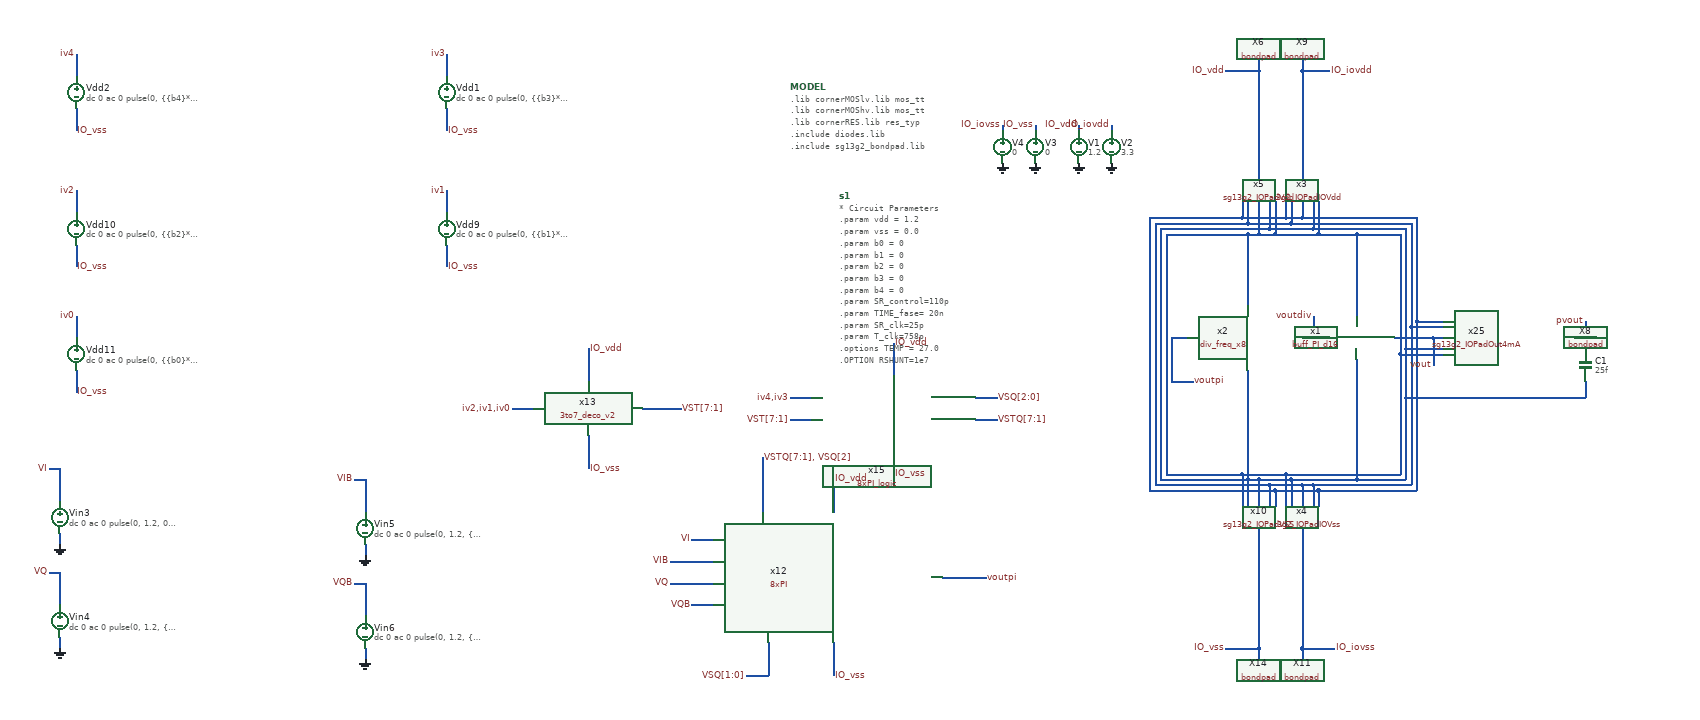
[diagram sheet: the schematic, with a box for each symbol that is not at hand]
v {xschem version=3.4.8RC file_version=1.2}
G {}
K {}
V {}
S {}
F {}
E {}
N 140 -660 220 -660 {lab=IO_vdd}
N 20 -680 240 -680 {lab=IO_iovss}
N 60 -200 240 -200 {lab=IO_iovss}
N 70 -190 250 -190 {lab=IO_iovdd}
N 60 -670 230 -670 {lab=IO_vss}
N -220 -210 -60 -210 {lab=IO_vss}
N 240 -490 240 -200 {lab=IO_iovss}
N -310 -860 -310 -850 {
lab=IO_iovdd}
N -510 -860 -510 -850 {
lab=IO_iovss}
N 10 -720 10 -690 {lab=IO_iovdd}
N -70 -690 10 -690 {lab=IO_iovdd}
N 20 -720 20 -680 {lab=IO_iovss}
N -60 -680 20 -680 {lab=IO_iovss}
N 60 -720 60 -670 {lab=IO_vss}
N -20 -670 60 -670 {lab=IO_vss}
N 70 -720 70 -660 {lab=IO_vdd}
N 40 -690 250 -690 {lab=IO_iovdd}
N 70 -190 70 -160 {lab=IO_iovdd}
N -10 -190 70 -190 {lab=IO_iovdd}
N 60 -200 60 -160 {lab=IO_iovss}
N 40 -200 60 -200 {lab=IO_iovss}
N 10 -220 10 -160 {lab=IO_vdd}
N -70 -220 10 -220 {lab=IO_vdd}
N 40 -960 90 -960 {lab=IO_iovdd}
N 40 -980 40 -960 {lab=IO_iovdd}
N 40 -960 40 -690 {lab=IO_iovdd}
N 10 -690 40 -690 {lab=IO_iovdd}
N -70 -720 -70 -690 {lab=IO_iovdd}
N -240 -690 -70 -690 {lab=IO_iovdd}
N -60 -720 -60 -680 {lab=IO_iovss}
N -230 -680 -60 -680 {lab=IO_iovss}
N -20 -720 -20 -670 {lab=IO_vss}
N -220 -670 -20 -670 {lab=IO_vss}
N -10 -720 -10 -660 {lab=IO_vdd}
N -40 -960 -40 -660 {lab=IO_vdd}
N -60 -660 -40 -660 {lab=IO_vdd}
N -370 -860 -370 -850 {
lab=IO_vdd}
N -450 -860 -450 -850 {
lab=IO_vss}
N -10 -190 -10 -160 {lab=IO_iovdd}
N -240 -190 -10 -190 {lab=IO_iovdd}
N -20 -200 -20 -160 {lab=IO_iovss}
N -60 -210 -60 -160 {lab=IO_vss}
N -70 -220 -70 -160 {lab=IO_vdd}
N -210 -220 -70 -220 {lab=IO_vdd}
N -100 -960 -40 -960 {lab=IO_vdd}
N -40 -980 -40 -960 {lab=IO_vdd}
N 40 100 40 120 {lab=IO_iovss}
N -20 -200 40 -200 {lab=IO_iovss}
N -40 100 -40 120 {lab=IO_vss}
N 40 100 100 100 {lab=IO_iovss}
N 40 -200 40 100 {lab=IO_iovss}
N -100 100 -40 100 {lab=IO_vss}
N 10 -220 220 -220 {lab=IO_vdd}
N 250 -500 250 -190 {lab=IO_iovdd}
N 250 -500 300 -500 {lab=IO_iovdd}
N 250 -690 250 -500 {lab=IO_iovdd}
N 240 -490 300 -490 {lab=IO_iovss}
N 240 -680 240 -490 {lab=IO_iovss}
N 230 -450 300 -450 {lab=IO_vss}
N 230 -670 230 -450 {lab=IO_vss}
N 220 -440 300 -440 {lab=IO_vdd}
N 220 -660 220 -440 {lab=IO_vdd}
N 560 -470 580 -470 {lab=pvout}
N -240 -690 -240 -190 {lab=IO_iovdd}
N -230 -680 -230 -200 {lab=IO_iovss}
N -220 -670 -220 -210 {lab=IO_vss}
N -210 -660 -210 -220 {lab=IO_vdd}
N 560 -500 560 -470 {lab=pvout}
N 540 -470 560 -470 {lab=pvout}
N -230 -200 -20 -200 {lab=IO_iovss}
N -40 -210 -40 100 {lab=IO_vss}
N -60 -210 -40 -210 {lab=IO_vss}
N 20 -210 20 -160 {lab=IO_vss}
N 230 -360 230 -210 {lab=IO_vss}
N 560 -390 560 -360 {lab=IO_vss}
N 230 -360 560 -360 {lab=IO_vss}
N 230 -450 230 -360 {lab=IO_vss}
N 560 -470 560 -450 {lab=pvout}
N -40 -660 -10 -660 {lab=IO_vdd}
N 220 -440 220 -220 {lab=IO_vdd}
N 140 -210 230 -210 {lab=IO_vss}
N -10 -660 70 -660 {lab=IO_vdd}
N -40 -210 20 -210 {lab=IO_vss}
N -60 -410 -60 -210 {lab=IO_vss}
N 60 -470 90 -470 {lab=voutdiv}
N 140 -430 140 -210 {lab=IO_vss}
N 60 -510 60 -470 {lab=voutdiv}
N -200 -470 -170 -470 {lab=voutpi}
N 40 -470 60 -470 {lab=voutdiv}
N -200 -470 -200 -390 {lab=voutpi}
N -200 -390 -160 -390 {lab=voutpi}
N 280 -470 300 -470 {lab=vout}
N 280 -470 280 -420 {lab=vout}
N 210 -470 280 -470 {lab=vout}
N -60 -660 -60 -530 {lab=IO_vdd}
N -210 -660 -60 -660 {lab=IO_vdd}
N 140 -660 140 -510 {lab=IO_vdd}
N 70 -660 140 -660 {lab=IO_vdd}
N 20 -210 140 -210 {lab=IO_vss}
N -950 -250 -950 -150 {lab="VSTQ[7:1], VSQ[2]"}
N -1170 -340 -1100 -340 {lab=VST[7:1]}
N -820 -210 -820 -150 {lab=IO_vdd}
N -820 90 -820 150 {lab=IO_vss}
N -620 -30 -540 -30 {lab=voutpi}
N -710 -280 -710 -220 {lab=IO_vss}
N -1270 -450 -1270 -390 {lab=IO_vdd}
N -1410 -340 -1370 -340 {lab=iv2,iv1,iv0}
N -940 90 -940 150 {lab=VSQ[1:0]}
N -980 150 -940 150 {lab=VSQ[1:0]}
N -900 -360 -860 -360 {lab=iv4,iv3}
N -560 -360 -520 -360 {lab=VSQ[2:0]}
N -900 -320 -860 -320 {lab=VST[7:1]}
N -560 -320 -520 -320 {lab=VSTQ[7:1]}
N -710 -460 -710 -400 {lab=IO_vdd}
N -1270 -290 -1270 -230 {lab=IO_vss}
N -1080 -100 -1040 -100 {lab=VI}
N -1120 -60 -1040 -60 {lab=VIB}
N -1080 20 -1040 20 {lab=VQB}
N -1120 -20 -1040 -20 {lab=VQ}
N -2240 -110 -2240 -90 {
lab=GND}
N -2240 -230 -2240 -170 {
lab=VI}
N -2260 -230 -2240 -230 {
lab=VI}
N -2240 80 -2240 100 {
lab=GND}
N -2240 -40 -2240 20 {
lab=VQ}
N -2260 -40 -2240 -40 {
lab=VQ}
N -1680 -90 -1680 -70 {
lab=GND}
N -1680 -210 -1680 -150 {
lab=VIB}
N -1700 -210 -1680 -210 {
lab=VIB}
N -1680 -20 -1680 40 {
lab=VQB}
N -1700 -20 -1680 -20 {
lab=VQB}
N -1680 100 -1680 120 {
lab=GND}
N -2210 -740 -2210 -700 {lab=iv2}
N -1530 -740 -1530 -700 {lab=iv1}
N -2210 -640 -2210 -600 {lab=IO_vss}
N -1530 -640 -1530 -600 {lab=IO_vss}
N -2210 -510 -2210 -470 {lab=iv0}
N -2210 -410 -2210 -370 {lab=IO_vss}
N -2210 -990 -2210 -950 {lab=iv4}
N -1530 -990 -1530 -950 {lab=iv3}
N -1530 -890 -1530 -850 {lab=IO_vss}
N -2210 -890 -2210 -850 {lab=IO_vss}
C {devices/lab_pin.sym} 560 -500 1 0 {name=p22 sig_type=std_logic lab=pvout
}
C {netlist_not_shown.sym} -810 -730 0 0 {name=s1 only_toplevel=true 

value="

* Circuit Parameters
.param vdd = 1.2
.param vss = 0.0
.param b0 = 0
.param b1 = 0
.param b2 = 0
.param b3 = 0
.param b4 = 0
.param SR_control=110p
.param TIME_fase= 20n
.param SR_clk=25p
.param T_clk=758p
.options TEMP = 27.0
.OPTION RSHUNT=1e7
.OPTION CSHUNT=1e-15
.option rseries = 1e-4
.option ITL1 = 200
.option ITL2 = 600
.options method=gear reltol=1e-2 abstol=1e-3 vntol=1e-4
.options gmin=3e-8


* 	Initial Conditions
* Inputs and IOCells
.nodeset v(IO_iovdd)=3.3 v(IO_vdd)=1.2 v(IO_vss)=0 v(IO_iovss)=0

* OP Parameters & Singals to save
.save V(vout) V(voutpi) V(voutdiv) V(pvout)


*Simulations
.control
set ngdebug
set verbose
let simul = 0
while simul < 32
	echo Simulando la fase $&simul
	alterparam b0 = $&simul%2
	alterparam b1 = floor($&simul/2)%2
	alterparam b2 = floor($&simul/4)%2
	alterparam b3 = floor($&simul/8)%2
	alterparam b4 = floor($&simul/16)%2
	reset
	tran 5PS 20NS
	display
	set filetype = ascii
	write tran_io_fase_OCell\{$&simul\}.raw
	let simul = simul+1
	end
.endc
.end"}
C {lab_pin.sym} 90 -960 2 0 {name=p23 sig_type=std_logic lab=IO_iovdd}
C {project_io/sg13g2_IOPadIOVdd/sg13g2_IOPadIOVdd.sym} 40 -840 3 0 {name=x3}
C {project_io/sg13g2_IOPadIOVss/sg13g2_IOPadIOVss.sym} 40 -40 1 0 {name=x4}
C {sg13g2_pr/bondpad.sym} 620 -470 1 0 {name=X8
model=bondpad
spiceprefix=X
size=80u
shape=0
padtype=0
}
C {sg13g2_pr/bondpad.sym} 40 -1020 0 0 {name=X9
model=bondpad
spiceprefix=X
size=80u
shape=0
padtype=0
}
C {vsource.sym} -310 -820 0 0 {name=V2 value=3.3
}
C {gnd.sym} -310 -790 0 0 {name=l5 lab=GND}
C {lab_pin.sym} -310 -860 1 0 {name=p31 sig_type=std_logic lab=IO_iovdd}
C {vsource.sym} -510 -820 0 0 {name=V4 value=0 savecurrent=false}
C {gnd.sym} -510 -790 0 0 {name=l8 lab=GND}
C {lab_pin.sym} -510 -860 1 0 {name=p35 sig_type=std_logic lab=IO_iovss}
C {project_io/sg13g2_IOPadVdd/sg13g2_IOPadVdd.sym} -40 -840 3 0 {name=x5}
C {sg13g2_pr/bondpad.sym} -40 -1020 0 0 {name=X6
model=bondpad
spiceprefix=X
size=80u
shape=0
padtype=0
}
C {vsource.sym} -370 -820 0 0 {name=V1 value=1.2}
C {gnd.sym} -370 -790 0 0 {name=l3 lab=GND}
C {lab_pin.sym} -370 -860 1 0 {name=p17 sig_type=std_logic lab=IO_vdd}
C {vsource.sym} -450 -820 0 0 {name=V3 value=0 savecurrent=false}
C {gnd.sym} -450 -790 0 0 {name=l7 lab=GND}
C {lab_pin.sym} -450 -860 1 0 {name=p25 sig_type=std_logic lab=IO_vss}
C {project_io/sg13g2_IOPadVSS/sg13g2_IOPadVSS.sym} -40 -40 1 0 {name=x10}
C {lab_pin.sym} -100 -960 0 0 {name=p26 sig_type=std_logic lab=IO_vdd}
C {sg13g2_pr/bondpad.sym} 40 160 2 0 {name=X11
model=bondpad
spiceprefix=X
size=80u
shape=0
padtype=0
}
C {sg13g2_pr/bondpad.sym} -40 160 2 0 {name=X14
model=bondpad
spiceprefix=X
size=80u
shape=0
padtype=0
}
C {lab_pin.sym} 100 100 2 0 {name=p29 sig_type=std_logic lab=IO_iovss}
C {lab_pin.sym} -100 100 0 0 {name=p34 sig_type=std_logic lab=IO_vss}
C {devices/lab_pin.sym} 280 -420 3 0 {name=p27 sig_type=std_logic lab=vout}
C {devices/code_shown.sym} -900 -930 0 0 {name=MODEL only_toplevel=true
format="tcleval( @value )"
value="
.lib cornerMOSlv.lib mos_tt
.lib cornerMOShv.lib mos_tt
.lib cornerRES.lib res_typ
.include diodes.lib
.include sg13g2_bondpad.lib
"}
C {capa.sym} 560 -420 0 0 {name=C1
m=1
value=25f
footprint=1206
device="ceramic capacitor"
}
C {project_io/sg13g2_IOPadOut4mA/sg13g2_IOPadOut4mA.sym} 420 -470 0 0 {name=x25
}
C {buff_PI_d16/buff_PI_d16.sym} 140 -470 0 0 {name=x1}
C {lab_pin.sym} -160 -390 2 0 {name=p6 sig_type=std_logic lab=voutpi}
C {div_freq_x8/div_freq_x8.sym} -190 -400 0 0 {name=x2}
C {lab_pin.sym} 60 -510 1 0 {name=p7 sig_type=std_logic lab=voutdiv}
C {8xPI/8xPI.sym} -1060 110 0 0 {name=x12}
C {3to7_deco_v2/3to7_deco_v2.sym} -1400 -270 0 0 {name=x13}
C {devices/lab_pin.sym} -1410 -340 0 0 {name=p12 sig_type=std_logic lab="iv2,iv1,iv0"}
C {devices/lab_pin.sym} -900 -360 0 0 {name=p13 sig_type=std_logic lab="iv4,iv3"}
C {devices/lab_pin.sym} -1100 -340 2 0 {name=p14 sig_type=std_logic lab=VST[7:1]}
C {devices/lab_pin.sym} -950 -250 2 0 {name=p15 sig_type=std_logic lab="VSTQ[7:1], VSQ[2]"}
C {8xPI_logic/8xPI_logic.sym} -710 -340 0 0 {name=x15}
C {devices/lab_pin.sym} -520 -360 2 0 {name=p16 sig_type=std_logic lab=VSQ[2:0]}
C {devices/lab_pin.sym} -980 150 0 0 {name=p9 sig_type=std_logic lab=VSQ[1:0]}
C {devices/lab_pin.sym} -900 -320 0 0 {name=p18 sig_type=std_logic lab=VST[7:1]}
C {devices/lab_pin.sym} -520 -320 2 0 {name=p19 sig_type=std_logic lab=VSTQ[7:1]}
C {devices/lab_pin.sym} -1080 -100 0 0 {name=p11 sig_type=std_logic lab=VI}
C {devices/lab_pin.sym} -1120 -60 0 0 {name=p24 sig_type=std_logic lab=VIB}
C {devices/lab_pin.sym} -1080 20 0 0 {name=p28 sig_type=std_logic lab=VQB}
C {devices/lab_pin.sym} -1120 -20 0 0 {name=p30 sig_type=std_logic lab=VQ}
C {lab_pin.sym} -540 -30 2 0 {name=p2 sig_type=std_logic lab=voutpi}
C {lab_pin.sym} -820 -210 2 0 {name=p1 sig_type=std_logic lab=IO_vdd}
C {lab_pin.sym} -710 -220 2 0 {name=p4 sig_type=std_logic lab=IO_vss}
C {lab_pin.sym} -710 -460 2 0 {name=p5 sig_type=std_logic lab=IO_vdd}
C {lab_pin.sym} -1270 -450 2 0 {name=p8 sig_type=std_logic lab=IO_vdd}
C {lab_pin.sym} -1270 -230 2 0 {name=p10 sig_type=std_logic lab=IO_vss}
C {lab_pin.sym} -820 150 2 0 {name=p3 sig_type=std_logic lab=IO_vss}
C {devices/gnd.sym} -2240 -90 0 0 {name=l2 lab=GND}
C {devices/vsource.sym} -2240 -140 0 0 {name=Vin3 value="dc 0 ac 0 pulse(0, 1.2, 0, SR_clk, SR_clk, \{T_clk/2-SR_clk\}, \{T_clk\}) "}
C {devices/lab_pin.sym} -2260 -230 0 0 {name=p20 sig_type=std_logic lab=VI}
C {devices/lab_pin.sym} -2260 -40 0 0 {name=p21 sig_type=std_logic lab=VQ}
C {devices/vsource.sym} -2240 50 0 0 {name=Vin4 value="dc 0 ac 0 pulse(0, 1.2, \{T_clk/4\}, \{SR_clk\}, \{SR_clk\}, \{T_clk/2-SR_clk\}, \{T_clk\}) "}
C {devices/gnd.sym} -1680 -70 0 0 {name=l4 lab=GND}
C {devices/vsource.sym} -1680 -120 0 0 {name=Vin5 value="dc 0 ac 0 pulse(0, 1.2, \{T_clk/2\}, \{SR_clk\}, \{SR_clk\}, \{T_clk/2-SR_clk\}, \{T_clk\}) "}
C {devices/lab_pin.sym} -1700 -210 0 0 {name=p32 sig_type=std_logic lab=VIB}
C {devices/vsource.sym} -1680 70 0 0 {name=Vin6 value="dc 0 ac 0 pulse(0, 1.2, \{T_clk*0.75\}, \{SR_clk\}, \{SR_clk\}, \{T_clk/2-SR_clk\}, \{T_clk\}) "}
C {devices/lab_pin.sym} -1700 -20 0 0 {name=p33 sig_type=std_logic lab=VQB}
C {devices/gnd.sym} -2240 100 0 0 {name=l1 lab=GND}
C {devices/gnd.sym} -1680 120 0 0 {name=l6 lab=GND}
C {devices/vsource.sym} -1530 -670 0 0 {name=Vdd9 value="dc 0 ac 0 pulse(0, \{\{b1\}*1.2\}, 0,\{SR_control\},\{SR_control\}, \{2*\{TIME_fase\}\}, \{4*\{TIME_fase\}\})"}
C {devices/vsource.sym} -2210 -670 0 0 {name=Vdd10 value="dc 0 ac 0 pulse(0, \{\{b2\}*1.2\}, 0,\{SR_control\},\{SR_control\}, \{4*\{TIME_fase\}\}, \{8*\{TIME_fase\}\}) "}
C {devices/lab_pin.sym} -2210 -740 0 0 {name=p49 sig_type=std_logic lab=iv2}
C {devices/lab_pin.sym} -1530 -740 0 0 {name=p50 sig_type=std_logic lab=iv1}
C {devices/lab_pin.sym} -2210 -600 2 0 {name=p51 sig_type=std_logic lab=IO_vss}
C {devices/lab_pin.sym} -1530 -600 2 0 {name=p52 sig_type=std_logic lab=IO_vss}
C {devices/vsource.sym} -2210 -440 0 0 {name=Vdd11 value="dc 0 ac 0 pulse(0, \{\{b0\}*1.2\}, 0,\{SR_control\},\{SR_control\}, \{TIME_fase\}, \{2*\{TIME_fase\}\})"}
C {devices/lab_pin.sym} -2210 -510 0 0 {name=p53 sig_type=std_logic lab=iv0}
C {devices/lab_pin.sym} -2210 -370 2 0 {name=p54 sig_type=std_logic lab=IO_vss}
C {devices/vsource.sym} -1530 -920 0 0 {name=Vdd1 value="dc 0 ac 0 pulse(0, \{\{b3\}*1.2\}, 0,\{SR_control\},\{SR_control\}, \{8*\{TIME_fase\}\}, \{16*\{TIME_fase\}\})"}
C {devices/vsource.sym} -2210 -920 0 0 {name=Vdd2 value="dc 0 ac 0 pulse(0, \{\{b4\}*1.2\}, 0,\{SR_control\},\{SR_control\}, \{16*\{TIME_fase\}\}, \{32*\{TIME_fase\}\}) "}
C {devices/lab_pin.sym} -2210 -990 0 0 {name=p36 sig_type=std_logic lab=iv4}
C {devices/lab_pin.sym} -1530 -990 0 0 {name=p37 sig_type=std_logic lab=iv3}
C {devices/lab_pin.sym} -2210 -850 2 0 {name=p38 sig_type=std_logic lab=IO_vss}
C {devices/lab_pin.sym} -1530 -850 2 0 {name=p39 sig_type=std_logic lab=IO_vss}
